# Generated by FakeRAM 2.0
VERSION 5.7 ;
BUSBITCHARS "[]" ;
PROPERTYDEFINITIONS
  MACRO width INTEGER ;
  MACRO depth INTEGER ;
  MACRO banks INTEGER ;
END PROPERTYDEFINITIONS
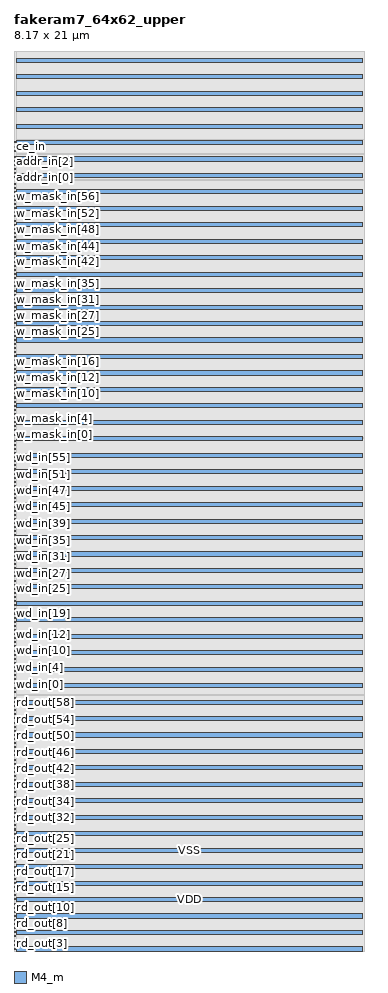
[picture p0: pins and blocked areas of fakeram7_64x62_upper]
MACRO fakeram7_64x62_upper
  PROPERTY width 62 ;
  PROPERTY depth 64 ;
  PROPERTY banks 2 ;
  FOREIGN fakeram7_64x62_upper 0 0 ;
  SYMMETRY X R90 ;
  SIZE 8.170 BY 21.000 ;
  CLASS COVER ;
  PIN rd_out[0]
    DIRECTION OUTPUT ;
    USE SIGNAL ;
    SHAPE ABUTMENT ;
    PORT
      LAYER M4_m ;
      RECT 0.000 0.039 0.024 0.063 ;
    END
  END rd_out[0]
  PIN rd_out[1]
    DIRECTION OUTPUT ;
    USE SIGNAL ;
    SHAPE ABUTMENT ;
    PORT
      LAYER M4_m ;
      RECT 0.000 0.135 0.024 0.159 ;
    END
  END rd_out[1]
  PIN rd_out[2]
    DIRECTION OUTPUT ;
    USE SIGNAL ;
    SHAPE ABUTMENT ;
    PORT
      LAYER M4_m ;
      RECT 0.000 0.231 0.024 0.255 ;
    END
  END rd_out[2]
  PIN rd_out[3]
    DIRECTION OUTPUT ;
    USE SIGNAL ;
    SHAPE ABUTMENT ;
    PORT
      LAYER M4_m ;
      RECT 0.000 0.327 0.024 0.351 ;
    END
  END rd_out[3]
  PIN rd_out[4]
    DIRECTION OUTPUT ;
    USE SIGNAL ;
    SHAPE ABUTMENT ;
    PORT
      LAYER M4_m ;
      RECT 0.000 0.423 0.024 0.447 ;
    END
  END rd_out[4]
  PIN rd_out[5]
    DIRECTION OUTPUT ;
    USE SIGNAL ;
    SHAPE ABUTMENT ;
    PORT
      LAYER M4_m ;
      RECT 0.000 0.519 0.024 0.543 ;
    END
  END rd_out[5]
  PIN rd_out[6]
    DIRECTION OUTPUT ;
    USE SIGNAL ;
    SHAPE ABUTMENT ;
    PORT
      LAYER M4_m ;
      RECT 0.000 0.615 0.024 0.639 ;
    END
  END rd_out[6]
  PIN rd_out[7]
    DIRECTION OUTPUT ;
    USE SIGNAL ;
    SHAPE ABUTMENT ;
    PORT
      LAYER M4_m ;
      RECT 0.000 0.711 0.024 0.735 ;
    END
  END rd_out[7]
  PIN rd_out[8]
    DIRECTION OUTPUT ;
    USE SIGNAL ;
    SHAPE ABUTMENT ;
    PORT
      LAYER M4_m ;
      RECT 0.000 0.807 0.024 0.831 ;
    END
  END rd_out[8]
  PIN rd_out[9]
    DIRECTION OUTPUT ;
    USE SIGNAL ;
    SHAPE ABUTMENT ;
    PORT
      LAYER M4_m ;
      RECT 0.000 0.903 0.024 0.927 ;
    END
  END rd_out[9]
  PIN rd_out[10]
    DIRECTION OUTPUT ;
    USE SIGNAL ;
    SHAPE ABUTMENT ;
    PORT
      LAYER M4_m ;
      RECT 0.000 0.999 0.024 1.023 ;
    END
  END rd_out[10]
  PIN rd_out[11]
    DIRECTION OUTPUT ;
    USE SIGNAL ;
    SHAPE ABUTMENT ;
    PORT
      LAYER M4_m ;
      RECT 0.000 1.095 0.024 1.119 ;
    END
  END rd_out[11]
  PIN rd_out[12]
    DIRECTION OUTPUT ;
    USE SIGNAL ;
    SHAPE ABUTMENT ;
    PORT
      LAYER M4_m ;
      RECT 0.000 1.191 0.024 1.215 ;
    END
  END rd_out[12]
  PIN rd_out[13]
    DIRECTION OUTPUT ;
    USE SIGNAL ;
    SHAPE ABUTMENT ;
    PORT
      LAYER M4_m ;
      RECT 0.000 1.287 0.024 1.311 ;
    END
  END rd_out[13]
  PIN rd_out[14]
    DIRECTION OUTPUT ;
    USE SIGNAL ;
    SHAPE ABUTMENT ;
    PORT
      LAYER M4_m ;
      RECT 0.000 1.383 0.024 1.407 ;
    END
  END rd_out[14]
  PIN rd_out[15]
    DIRECTION OUTPUT ;
    USE SIGNAL ;
    SHAPE ABUTMENT ;
    PORT
      LAYER M4_m ;
      RECT 0.000 1.479 0.024 1.503 ;
    END
  END rd_out[15]
  PIN rd_out[16]
    DIRECTION OUTPUT ;
    USE SIGNAL ;
    SHAPE ABUTMENT ;
    PORT
      LAYER M4_m ;
      RECT 0.000 1.575 0.024 1.599 ;
    END
  END rd_out[16]
  PIN rd_out[17]
    DIRECTION OUTPUT ;
    USE SIGNAL ;
    SHAPE ABUTMENT ;
    PORT
      LAYER M4_m ;
      RECT 0.000 1.671 0.024 1.695 ;
    END
  END rd_out[17]
  PIN rd_out[18]
    DIRECTION OUTPUT ;
    USE SIGNAL ;
    SHAPE ABUTMENT ;
    PORT
      LAYER M4_m ;
      RECT 0.000 1.767 0.024 1.791 ;
    END
  END rd_out[18]
  PIN rd_out[19]
    DIRECTION OUTPUT ;
    USE SIGNAL ;
    SHAPE ABUTMENT ;
    PORT
      LAYER M4_m ;
      RECT 0.000 1.863 0.024 1.887 ;
    END
  END rd_out[19]
  PIN rd_out[20]
    DIRECTION OUTPUT ;
    USE SIGNAL ;
    SHAPE ABUTMENT ;
    PORT
      LAYER M4_m ;
      RECT 0.000 1.959 0.024 1.983 ;
    END
  END rd_out[20]
  PIN rd_out[21]
    DIRECTION OUTPUT ;
    USE SIGNAL ;
    SHAPE ABUTMENT ;
    PORT
      LAYER M4_m ;
      RECT 0.000 2.055 0.024 2.079 ;
    END
  END rd_out[21]
  PIN rd_out[22]
    DIRECTION OUTPUT ;
    USE SIGNAL ;
    SHAPE ABUTMENT ;
    PORT
      LAYER M4_m ;
      RECT 0.000 2.151 0.024 2.175 ;
    END
  END rd_out[22]
  PIN rd_out[23]
    DIRECTION OUTPUT ;
    USE SIGNAL ;
    SHAPE ABUTMENT ;
    PORT
      LAYER M4_m ;
      RECT 0.000 2.247 0.024 2.271 ;
    END
  END rd_out[23]
  PIN rd_out[24]
    DIRECTION OUTPUT ;
    USE SIGNAL ;
    SHAPE ABUTMENT ;
    PORT
      LAYER M4_m ;
      RECT 0.000 2.343 0.024 2.367 ;
    END
  END rd_out[24]
  PIN rd_out[25]
    DIRECTION OUTPUT ;
    USE SIGNAL ;
    SHAPE ABUTMENT ;
    PORT
      LAYER M4_m ;
      RECT 0.000 2.439 0.024 2.463 ;
    END
  END rd_out[25]
  PIN rd_out[26]
    DIRECTION OUTPUT ;
    USE SIGNAL ;
    SHAPE ABUTMENT ;
    PORT
      LAYER M4_m ;
      RECT 0.000 2.535 0.024 2.559 ;
    END
  END rd_out[26]
  PIN rd_out[27]
    DIRECTION OUTPUT ;
    USE SIGNAL ;
    SHAPE ABUTMENT ;
    PORT
      LAYER M4_m ;
      RECT 0.000 2.631 0.024 2.655 ;
    END
  END rd_out[27]
  PIN rd_out[28]
    DIRECTION OUTPUT ;
    USE SIGNAL ;
    SHAPE ABUTMENT ;
    PORT
      LAYER M4_m ;
      RECT 0.000 2.727 0.024 2.751 ;
    END
  END rd_out[28]
  PIN rd_out[29]
    DIRECTION OUTPUT ;
    USE SIGNAL ;
    SHAPE ABUTMENT ;
    PORT
      LAYER M4_m ;
      RECT 0.000 2.823 0.024 2.847 ;
    END
  END rd_out[29]
  PIN rd_out[30]
    DIRECTION OUTPUT ;
    USE SIGNAL ;
    SHAPE ABUTMENT ;
    PORT
      LAYER M4_m ;
      RECT 0.000 2.919 0.024 2.943 ;
    END
  END rd_out[30]
  PIN rd_out[31]
    DIRECTION OUTPUT ;
    USE SIGNAL ;
    SHAPE ABUTMENT ;
    PORT
      LAYER M4_m ;
      RECT 0.000 3.015 0.024 3.039 ;
    END
  END rd_out[31]
  PIN rd_out[32]
    DIRECTION OUTPUT ;
    USE SIGNAL ;
    SHAPE ABUTMENT ;
    PORT
      LAYER M4_m ;
      RECT 0.000 3.111 0.024 3.135 ;
    END
  END rd_out[32]
  PIN rd_out[33]
    DIRECTION OUTPUT ;
    USE SIGNAL ;
    SHAPE ABUTMENT ;
    PORT
      LAYER M4_m ;
      RECT 0.000 3.207 0.024 3.231 ;
    END
  END rd_out[33]
  PIN rd_out[34]
    DIRECTION OUTPUT ;
    USE SIGNAL ;
    SHAPE ABUTMENT ;
    PORT
      LAYER M4_m ;
      RECT 0.000 3.303 0.024 3.327 ;
    END
  END rd_out[34]
  PIN rd_out[35]
    DIRECTION OUTPUT ;
    USE SIGNAL ;
    SHAPE ABUTMENT ;
    PORT
      LAYER M4_m ;
      RECT 0.000 3.399 0.024 3.423 ;
    END
  END rd_out[35]
  PIN rd_out[36]
    DIRECTION OUTPUT ;
    USE SIGNAL ;
    SHAPE ABUTMENT ;
    PORT
      LAYER M4_m ;
      RECT 0.000 3.495 0.024 3.519 ;
    END
  END rd_out[36]
  PIN rd_out[37]
    DIRECTION OUTPUT ;
    USE SIGNAL ;
    SHAPE ABUTMENT ;
    PORT
      LAYER M4_m ;
      RECT 0.000 3.591 0.024 3.615 ;
    END
  END rd_out[37]
  PIN rd_out[38]
    DIRECTION OUTPUT ;
    USE SIGNAL ;
    SHAPE ABUTMENT ;
    PORT
      LAYER M4_m ;
      RECT 0.000 3.687 0.024 3.711 ;
    END
  END rd_out[38]
  PIN rd_out[39]
    DIRECTION OUTPUT ;
    USE SIGNAL ;
    SHAPE ABUTMENT ;
    PORT
      LAYER M4_m ;
      RECT 0.000 3.783 0.024 3.807 ;
    END
  END rd_out[39]
  PIN rd_out[40]
    DIRECTION OUTPUT ;
    USE SIGNAL ;
    SHAPE ABUTMENT ;
    PORT
      LAYER M4_m ;
      RECT 0.000 3.879 0.024 3.903 ;
    END
  END rd_out[40]
  PIN rd_out[41]
    DIRECTION OUTPUT ;
    USE SIGNAL ;
    SHAPE ABUTMENT ;
    PORT
      LAYER M4_m ;
      RECT 0.000 3.975 0.024 3.999 ;
    END
  END rd_out[41]
  PIN rd_out[42]
    DIRECTION OUTPUT ;
    USE SIGNAL ;
    SHAPE ABUTMENT ;
    PORT
      LAYER M4_m ;
      RECT 0.000 4.071 0.024 4.095 ;
    END
  END rd_out[42]
  PIN rd_out[43]
    DIRECTION OUTPUT ;
    USE SIGNAL ;
    SHAPE ABUTMENT ;
    PORT
      LAYER M4_m ;
      RECT 0.000 4.167 0.024 4.191 ;
    END
  END rd_out[43]
  PIN rd_out[44]
    DIRECTION OUTPUT ;
    USE SIGNAL ;
    SHAPE ABUTMENT ;
    PORT
      LAYER M4_m ;
      RECT 0.000 4.263 0.024 4.287 ;
    END
  END rd_out[44]
  PIN rd_out[45]
    DIRECTION OUTPUT ;
    USE SIGNAL ;
    SHAPE ABUTMENT ;
    PORT
      LAYER M4_m ;
      RECT 0.000 4.359 0.024 4.383 ;
    END
  END rd_out[45]
  PIN rd_out[46]
    DIRECTION OUTPUT ;
    USE SIGNAL ;
    SHAPE ABUTMENT ;
    PORT
      LAYER M4_m ;
      RECT 0.000 4.455 0.024 4.479 ;
    END
  END rd_out[46]
  PIN rd_out[47]
    DIRECTION OUTPUT ;
    USE SIGNAL ;
    SHAPE ABUTMENT ;
    PORT
      LAYER M4_m ;
      RECT 0.000 4.551 0.024 4.575 ;
    END
  END rd_out[47]
  PIN rd_out[48]
    DIRECTION OUTPUT ;
    USE SIGNAL ;
    SHAPE ABUTMENT ;
    PORT
      LAYER M4_m ;
      RECT 0.000 4.647 0.024 4.671 ;
    END
  END rd_out[48]
  PIN rd_out[49]
    DIRECTION OUTPUT ;
    USE SIGNAL ;
    SHAPE ABUTMENT ;
    PORT
      LAYER M4_m ;
      RECT 0.000 4.743 0.024 4.767 ;
    END
  END rd_out[49]
  PIN rd_out[50]
    DIRECTION OUTPUT ;
    USE SIGNAL ;
    SHAPE ABUTMENT ;
    PORT
      LAYER M4_m ;
      RECT 0.000 4.839 0.024 4.863 ;
    END
  END rd_out[50]
  PIN rd_out[51]
    DIRECTION OUTPUT ;
    USE SIGNAL ;
    SHAPE ABUTMENT ;
    PORT
      LAYER M4_m ;
      RECT 0.000 4.935 0.024 4.959 ;
    END
  END rd_out[51]
  PIN rd_out[52]
    DIRECTION OUTPUT ;
    USE SIGNAL ;
    SHAPE ABUTMENT ;
    PORT
      LAYER M4_m ;
      RECT 0.000 5.031 0.024 5.055 ;
    END
  END rd_out[52]
  PIN rd_out[53]
    DIRECTION OUTPUT ;
    USE SIGNAL ;
    SHAPE ABUTMENT ;
    PORT
      LAYER M4_m ;
      RECT 0.000 5.127 0.024 5.151 ;
    END
  END rd_out[53]
  PIN rd_out[54]
    DIRECTION OUTPUT ;
    USE SIGNAL ;
    SHAPE ABUTMENT ;
    PORT
      LAYER M4_m ;
      RECT 0.000 5.223 0.024 5.247 ;
    END
  END rd_out[54]
  PIN rd_out[55]
    DIRECTION OUTPUT ;
    USE SIGNAL ;
    SHAPE ABUTMENT ;
    PORT
      LAYER M4_m ;
      RECT 0.000 5.319 0.024 5.343 ;
    END
  END rd_out[55]
  PIN rd_out[56]
    DIRECTION OUTPUT ;
    USE SIGNAL ;
    SHAPE ABUTMENT ;
    PORT
      LAYER M4_m ;
      RECT 0.000 5.415 0.024 5.439 ;
    END
  END rd_out[56]
  PIN rd_out[57]
    DIRECTION OUTPUT ;
    USE SIGNAL ;
    SHAPE ABUTMENT ;
    PORT
      LAYER M4_m ;
      RECT 0.000 5.511 0.024 5.535 ;
    END
  END rd_out[57]
  PIN rd_out[58]
    DIRECTION OUTPUT ;
    USE SIGNAL ;
    SHAPE ABUTMENT ;
    PORT
      LAYER M4_m ;
      RECT 0.000 5.607 0.024 5.631 ;
    END
  END rd_out[58]
  PIN rd_out[59]
    DIRECTION OUTPUT ;
    USE SIGNAL ;
    SHAPE ABUTMENT ;
    PORT
      LAYER M4_m ;
      RECT 0.000 5.703 0.024 5.727 ;
    END
  END rd_out[59]
  PIN rd_out[60]
    DIRECTION OUTPUT ;
    USE SIGNAL ;
    SHAPE ABUTMENT ;
    PORT
      LAYER M4_m ;
      RECT 0.000 5.799 0.024 5.823 ;
    END
  END rd_out[60]
  PIN rd_out[61]
    DIRECTION OUTPUT ;
    USE SIGNAL ;
    SHAPE ABUTMENT ;
    PORT
      LAYER M4_m ;
      RECT 0.000 5.895 0.024 5.919 ;
    END
  END rd_out[61]
  PIN wd_in[0]
    DIRECTION INPUT ;
    USE SIGNAL ;
    SHAPE ABUTMENT ;
    PORT
      LAYER M4_m ;
      RECT 0.000 6.039 0.024 6.063 ;
    END
  END wd_in[0]
  PIN wd_in[1]
    DIRECTION INPUT ;
    USE SIGNAL ;
    SHAPE ABUTMENT ;
    PORT
      LAYER M4_m ;
      RECT 0.000 6.135 0.024 6.159 ;
    END
  END wd_in[1]
  PIN wd_in[2]
    DIRECTION INPUT ;
    USE SIGNAL ;
    SHAPE ABUTMENT ;
    PORT
      LAYER M4_m ;
      RECT 0.000 6.231 0.024 6.255 ;
    END
  END wd_in[2]
  PIN wd_in[3]
    DIRECTION INPUT ;
    USE SIGNAL ;
    SHAPE ABUTMENT ;
    PORT
      LAYER M4_m ;
      RECT 0.000 6.327 0.024 6.351 ;
    END
  END wd_in[3]
  PIN wd_in[4]
    DIRECTION INPUT ;
    USE SIGNAL ;
    SHAPE ABUTMENT ;
    PORT
      LAYER M4_m ;
      RECT 0.000 6.423 0.024 6.447 ;
    END
  END wd_in[4]
  PIN wd_in[5]
    DIRECTION INPUT ;
    USE SIGNAL ;
    SHAPE ABUTMENT ;
    PORT
      LAYER M4_m ;
      RECT 0.000 6.519 0.024 6.543 ;
    END
  END wd_in[5]
  PIN wd_in[6]
    DIRECTION INPUT ;
    USE SIGNAL ;
    SHAPE ABUTMENT ;
    PORT
      LAYER M4_m ;
      RECT 0.000 6.615 0.024 6.639 ;
    END
  END wd_in[6]
  PIN wd_in[7]
    DIRECTION INPUT ;
    USE SIGNAL ;
    SHAPE ABUTMENT ;
    PORT
      LAYER M4_m ;
      RECT 0.000 6.711 0.024 6.735 ;
    END
  END wd_in[7]
  PIN wd_in[8]
    DIRECTION INPUT ;
    USE SIGNAL ;
    SHAPE ABUTMENT ;
    PORT
      LAYER M4_m ;
      RECT 0.000 6.807 0.024 6.831 ;
    END
  END wd_in[8]
  PIN wd_in[9]
    DIRECTION INPUT ;
    USE SIGNAL ;
    SHAPE ABUTMENT ;
    PORT
      LAYER M4_m ;
      RECT 0.000 6.903 0.024 6.927 ;
    END
  END wd_in[9]
  PIN wd_in[10]
    DIRECTION INPUT ;
    USE SIGNAL ;
    SHAPE ABUTMENT ;
    PORT
      LAYER M4_m ;
      RECT 0.000 6.999 0.024 7.023 ;
    END
  END wd_in[10]
  PIN wd_in[11]
    DIRECTION INPUT ;
    USE SIGNAL ;
    SHAPE ABUTMENT ;
    PORT
      LAYER M4_m ;
      RECT 0.000 7.095 0.024 7.119 ;
    END
  END wd_in[11]
  PIN wd_in[12]
    DIRECTION INPUT ;
    USE SIGNAL ;
    SHAPE ABUTMENT ;
    PORT
      LAYER M4_m ;
      RECT 0.000 7.191 0.024 7.215 ;
    END
  END wd_in[12]
  PIN wd_in[13]
    DIRECTION INPUT ;
    USE SIGNAL ;
    SHAPE ABUTMENT ;
    PORT
      LAYER M4_m ;
      RECT 0.000 7.287 0.024 7.311 ;
    END
  END wd_in[13]
  PIN wd_in[14]
    DIRECTION INPUT ;
    USE SIGNAL ;
    SHAPE ABUTMENT ;
    PORT
      LAYER M4_m ;
      RECT 0.000 7.383 0.024 7.407 ;
    END
  END wd_in[14]
  PIN wd_in[15]
    DIRECTION INPUT ;
    USE SIGNAL ;
    SHAPE ABUTMENT ;
    PORT
      LAYER M4_m ;
      RECT 0.000 7.479 0.024 7.503 ;
    END
  END wd_in[15]
  PIN wd_in[16]
    DIRECTION INPUT ;
    USE SIGNAL ;
    SHAPE ABUTMENT ;
    PORT
      LAYER M4_m ;
      RECT 0.000 7.575 0.024 7.599 ;
    END
  END wd_in[16]
  PIN wd_in[17]
    DIRECTION INPUT ;
    USE SIGNAL ;
    SHAPE ABUTMENT ;
    PORT
      LAYER M4_m ;
      RECT 0.000 7.671 0.024 7.695 ;
    END
  END wd_in[17]
  PIN wd_in[18]
    DIRECTION INPUT ;
    USE SIGNAL ;
    SHAPE ABUTMENT ;
    PORT
      LAYER M4_m ;
      RECT 0.000 7.767 0.024 7.791 ;
    END
  END wd_in[18]
  PIN wd_in[19]
    DIRECTION INPUT ;
    USE SIGNAL ;
    SHAPE ABUTMENT ;
    PORT
      LAYER M4_m ;
      RECT 0.000 7.863 0.024 7.887 ;
    END
  END wd_in[19]
  PIN wd_in[20]
    DIRECTION INPUT ;
    USE SIGNAL ;
    SHAPE ABUTMENT ;
    PORT
      LAYER M4_m ;
      RECT 0.000 7.959 0.024 7.983 ;
    END
  END wd_in[20]
  PIN wd_in[21]
    DIRECTION INPUT ;
    USE SIGNAL ;
    SHAPE ABUTMENT ;
    PORT
      LAYER M4_m ;
      RECT 0.000 8.055 0.024 8.079 ;
    END
  END wd_in[21]
  PIN wd_in[22]
    DIRECTION INPUT ;
    USE SIGNAL ;
    SHAPE ABUTMENT ;
    PORT
      LAYER M4_m ;
      RECT 0.000 8.151 0.024 8.175 ;
    END
  END wd_in[22]
  PIN wd_in[23]
    DIRECTION INPUT ;
    USE SIGNAL ;
    SHAPE ABUTMENT ;
    PORT
      LAYER M4_m ;
      RECT 0.000 8.247 0.024 8.271 ;
    END
  END wd_in[23]
  PIN wd_in[24]
    DIRECTION INPUT ;
    USE SIGNAL ;
    SHAPE ABUTMENT ;
    PORT
      LAYER M4_m ;
      RECT 0.000 8.343 0.024 8.367 ;
    END
  END wd_in[24]
  PIN wd_in[25]
    DIRECTION INPUT ;
    USE SIGNAL ;
    SHAPE ABUTMENT ;
    PORT
      LAYER M4_m ;
      RECT 0.000 8.439 0.024 8.463 ;
    END
  END wd_in[25]
  PIN wd_in[26]
    DIRECTION INPUT ;
    USE SIGNAL ;
    SHAPE ABUTMENT ;
    PORT
      LAYER M4_m ;
      RECT 0.000 8.535 0.024 8.559 ;
    END
  END wd_in[26]
  PIN wd_in[27]
    DIRECTION INPUT ;
    USE SIGNAL ;
    SHAPE ABUTMENT ;
    PORT
      LAYER M4_m ;
      RECT 0.000 8.631 0.024 8.655 ;
    END
  END wd_in[27]
  PIN wd_in[28]
    DIRECTION INPUT ;
    USE SIGNAL ;
    SHAPE ABUTMENT ;
    PORT
      LAYER M4_m ;
      RECT 0.000 8.727 0.024 8.751 ;
    END
  END wd_in[28]
  PIN wd_in[29]
    DIRECTION INPUT ;
    USE SIGNAL ;
    SHAPE ABUTMENT ;
    PORT
      LAYER M4_m ;
      RECT 0.000 8.823 0.024 8.847 ;
    END
  END wd_in[29]
  PIN wd_in[30]
    DIRECTION INPUT ;
    USE SIGNAL ;
    SHAPE ABUTMENT ;
    PORT
      LAYER M4_m ;
      RECT 0.000 8.919 0.024 8.943 ;
    END
  END wd_in[30]
  PIN wd_in[31]
    DIRECTION INPUT ;
    USE SIGNAL ;
    SHAPE ABUTMENT ;
    PORT
      LAYER M4_m ;
      RECT 0.000 9.015 0.024 9.039 ;
    END
  END wd_in[31]
  PIN wd_in[32]
    DIRECTION INPUT ;
    USE SIGNAL ;
    SHAPE ABUTMENT ;
    PORT
      LAYER M4_m ;
      RECT 0.000 9.111 0.024 9.135 ;
    END
  END wd_in[32]
  PIN wd_in[33]
    DIRECTION INPUT ;
    USE SIGNAL ;
    SHAPE ABUTMENT ;
    PORT
      LAYER M4_m ;
      RECT 0.000 9.207 0.024 9.231 ;
    END
  END wd_in[33]
  PIN wd_in[34]
    DIRECTION INPUT ;
    USE SIGNAL ;
    SHAPE ABUTMENT ;
    PORT
      LAYER M4_m ;
      RECT 0.000 9.303 0.024 9.327 ;
    END
  END wd_in[34]
  PIN wd_in[35]
    DIRECTION INPUT ;
    USE SIGNAL ;
    SHAPE ABUTMENT ;
    PORT
      LAYER M4_m ;
      RECT 0.000 9.399 0.024 9.423 ;
    END
  END wd_in[35]
  PIN wd_in[36]
    DIRECTION INPUT ;
    USE SIGNAL ;
    SHAPE ABUTMENT ;
    PORT
      LAYER M4_m ;
      RECT 0.000 9.495 0.024 9.519 ;
    END
  END wd_in[36]
  PIN wd_in[37]
    DIRECTION INPUT ;
    USE SIGNAL ;
    SHAPE ABUTMENT ;
    PORT
      LAYER M4_m ;
      RECT 0.000 9.591 0.024 9.615 ;
    END
  END wd_in[37]
  PIN wd_in[38]
    DIRECTION INPUT ;
    USE SIGNAL ;
    SHAPE ABUTMENT ;
    PORT
      LAYER M4_m ;
      RECT 0.000 9.687 0.024 9.711 ;
    END
  END wd_in[38]
  PIN wd_in[39]
    DIRECTION INPUT ;
    USE SIGNAL ;
    SHAPE ABUTMENT ;
    PORT
      LAYER M4_m ;
      RECT 0.000 9.783 0.024 9.807 ;
    END
  END wd_in[39]
  PIN wd_in[40]
    DIRECTION INPUT ;
    USE SIGNAL ;
    SHAPE ABUTMENT ;
    PORT
      LAYER M4_m ;
      RECT 0.000 9.879 0.024 9.903 ;
    END
  END wd_in[40]
  PIN wd_in[41]
    DIRECTION INPUT ;
    USE SIGNAL ;
    SHAPE ABUTMENT ;
    PORT
      LAYER M4_m ;
      RECT 0.000 9.975 0.024 9.999 ;
    END
  END wd_in[41]
  PIN wd_in[42]
    DIRECTION INPUT ;
    USE SIGNAL ;
    SHAPE ABUTMENT ;
    PORT
      LAYER M4_m ;
      RECT 0.000 10.071 0.024 10.095 ;
    END
  END wd_in[42]
  PIN wd_in[43]
    DIRECTION INPUT ;
    USE SIGNAL ;
    SHAPE ABUTMENT ;
    PORT
      LAYER M4_m ;
      RECT 0.000 10.167 0.024 10.191 ;
    END
  END wd_in[43]
  PIN wd_in[44]
    DIRECTION INPUT ;
    USE SIGNAL ;
    SHAPE ABUTMENT ;
    PORT
      LAYER M4_m ;
      RECT 0.000 10.263 0.024 10.287 ;
    END
  END wd_in[44]
  PIN wd_in[45]
    DIRECTION INPUT ;
    USE SIGNAL ;
    SHAPE ABUTMENT ;
    PORT
      LAYER M4_m ;
      RECT 0.000 10.359 0.024 10.383 ;
    END
  END wd_in[45]
  PIN wd_in[46]
    DIRECTION INPUT ;
    USE SIGNAL ;
    SHAPE ABUTMENT ;
    PORT
      LAYER M4_m ;
      RECT 0.000 10.455 0.024 10.479 ;
    END
  END wd_in[46]
  PIN wd_in[47]
    DIRECTION INPUT ;
    USE SIGNAL ;
    SHAPE ABUTMENT ;
    PORT
      LAYER M4_m ;
      RECT 0.000 10.551 0.024 10.575 ;
    END
  END wd_in[47]
  PIN wd_in[48]
    DIRECTION INPUT ;
    USE SIGNAL ;
    SHAPE ABUTMENT ;
    PORT
      LAYER M4_m ;
      RECT 0.000 10.647 0.024 10.671 ;
    END
  END wd_in[48]
  PIN wd_in[49]
    DIRECTION INPUT ;
    USE SIGNAL ;
    SHAPE ABUTMENT ;
    PORT
      LAYER M4_m ;
      RECT 0.000 10.743 0.024 10.767 ;
    END
  END wd_in[49]
  PIN wd_in[50]
    DIRECTION INPUT ;
    USE SIGNAL ;
    SHAPE ABUTMENT ;
    PORT
      LAYER M4_m ;
      RECT 0.000 10.839 0.024 10.863 ;
    END
  END wd_in[50]
  PIN wd_in[51]
    DIRECTION INPUT ;
    USE SIGNAL ;
    SHAPE ABUTMENT ;
    PORT
      LAYER M4_m ;
      RECT 0.000 10.935 0.024 10.959 ;
    END
  END wd_in[51]
  PIN wd_in[52]
    DIRECTION INPUT ;
    USE SIGNAL ;
    SHAPE ABUTMENT ;
    PORT
      LAYER M4_m ;
      RECT 0.000 11.031 0.024 11.055 ;
    END
  END wd_in[52]
  PIN wd_in[53]
    DIRECTION INPUT ;
    USE SIGNAL ;
    SHAPE ABUTMENT ;
    PORT
      LAYER M4_m ;
      RECT 0.000 11.127 0.024 11.151 ;
    END
  END wd_in[53]
  PIN wd_in[54]
    DIRECTION INPUT ;
    USE SIGNAL ;
    SHAPE ABUTMENT ;
    PORT
      LAYER M4_m ;
      RECT 0.000 11.223 0.024 11.247 ;
    END
  END wd_in[54]
  PIN wd_in[55]
    DIRECTION INPUT ;
    USE SIGNAL ;
    SHAPE ABUTMENT ;
    PORT
      LAYER M4_m ;
      RECT 0.000 11.319 0.024 11.343 ;
    END
  END wd_in[55]
  PIN wd_in[56]
    DIRECTION INPUT ;
    USE SIGNAL ;
    SHAPE ABUTMENT ;
    PORT
      LAYER M4_m ;
      RECT 0.000 11.415 0.024 11.439 ;
    END
  END wd_in[56]
  PIN wd_in[57]
    DIRECTION INPUT ;
    USE SIGNAL ;
    SHAPE ABUTMENT ;
    PORT
      LAYER M4_m ;
      RECT 0.000 11.511 0.024 11.535 ;
    END
  END wd_in[57]
  PIN wd_in[58]
    DIRECTION INPUT ;
    USE SIGNAL ;
    SHAPE ABUTMENT ;
    PORT
      LAYER M4_m ;
      RECT 0.000 11.607 0.024 11.631 ;
    END
  END wd_in[58]
  PIN wd_in[59]
    DIRECTION INPUT ;
    USE SIGNAL ;
    SHAPE ABUTMENT ;
    PORT
      LAYER M4_m ;
      RECT 0.000 11.703 0.024 11.727 ;
    END
  END wd_in[59]
  PIN wd_in[60]
    DIRECTION INPUT ;
    USE SIGNAL ;
    SHAPE ABUTMENT ;
    PORT
      LAYER M4_m ;
      RECT 0.000 11.799 0.024 11.823 ;
    END
  END wd_in[60]
  PIN wd_in[61]
    DIRECTION INPUT ;
    USE SIGNAL ;
    SHAPE ABUTMENT ;
    PORT
      LAYER M4_m ;
      RECT 0.000 11.895 0.024 11.919 ;
    END
  END wd_in[61]
  PIN w_mask_in[0]
    DIRECTION INPUT ;
    USE SIGNAL ;
    SHAPE ABUTMENT ;
    PORT
      LAYER M4_m ;
      RECT 0.000 12.039 0.024 12.063 ;
    END
  END w_mask_in[0]
  PIN w_mask_in[1]
    DIRECTION INPUT ;
    USE SIGNAL ;
    SHAPE ABUTMENT ;
    PORT
      LAYER M4_m ;
      RECT 0.000 12.135 0.024 12.159 ;
    END
  END w_mask_in[1]
  PIN w_mask_in[2]
    DIRECTION INPUT ;
    USE SIGNAL ;
    SHAPE ABUTMENT ;
    PORT
      LAYER M4_m ;
      RECT 0.000 12.231 0.024 12.255 ;
    END
  END w_mask_in[2]
  PIN w_mask_in[3]
    DIRECTION INPUT ;
    USE SIGNAL ;
    SHAPE ABUTMENT ;
    PORT
      LAYER M4_m ;
      RECT 0.000 12.327 0.024 12.351 ;
    END
  END w_mask_in[3]
  PIN w_mask_in[4]
    DIRECTION INPUT ;
    USE SIGNAL ;
    SHAPE ABUTMENT ;
    PORT
      LAYER M4_m ;
      RECT 0.000 12.423 0.024 12.447 ;
    END
  END w_mask_in[4]
  PIN w_mask_in[5]
    DIRECTION INPUT ;
    USE SIGNAL ;
    SHAPE ABUTMENT ;
    PORT
      LAYER M4_m ;
      RECT 0.000 12.519 0.024 12.543 ;
    END
  END w_mask_in[5]
  PIN w_mask_in[6]
    DIRECTION INPUT ;
    USE SIGNAL ;
    SHAPE ABUTMENT ;
    PORT
      LAYER M4_m ;
      RECT 0.000 12.615 0.024 12.639 ;
    END
  END w_mask_in[6]
  PIN w_mask_in[7]
    DIRECTION INPUT ;
    USE SIGNAL ;
    SHAPE ABUTMENT ;
    PORT
      LAYER M4_m ;
      RECT 0.000 12.711 0.024 12.735 ;
    END
  END w_mask_in[7]
  PIN w_mask_in[8]
    DIRECTION INPUT ;
    USE SIGNAL ;
    SHAPE ABUTMENT ;
    PORT
      LAYER M4_m ;
      RECT 0.000 12.807 0.024 12.831 ;
    END
  END w_mask_in[8]
  PIN w_mask_in[9]
    DIRECTION INPUT ;
    USE SIGNAL ;
    SHAPE ABUTMENT ;
    PORT
      LAYER M4_m ;
      RECT 0.000 12.903 0.024 12.927 ;
    END
  END w_mask_in[9]
  PIN w_mask_in[10]
    DIRECTION INPUT ;
    USE SIGNAL ;
    SHAPE ABUTMENT ;
    PORT
      LAYER M4_m ;
      RECT 0.000 12.999 0.024 13.023 ;
    END
  END w_mask_in[10]
  PIN w_mask_in[11]
    DIRECTION INPUT ;
    USE SIGNAL ;
    SHAPE ABUTMENT ;
    PORT
      LAYER M4_m ;
      RECT 0.000 13.095 0.024 13.119 ;
    END
  END w_mask_in[11]
  PIN w_mask_in[12]
    DIRECTION INPUT ;
    USE SIGNAL ;
    SHAPE ABUTMENT ;
    PORT
      LAYER M4_m ;
      RECT 0.000 13.191 0.024 13.215 ;
    END
  END w_mask_in[12]
  PIN w_mask_in[13]
    DIRECTION INPUT ;
    USE SIGNAL ;
    SHAPE ABUTMENT ;
    PORT
      LAYER M4_m ;
      RECT 0.000 13.287 0.024 13.311 ;
    END
  END w_mask_in[13]
  PIN w_mask_in[14]
    DIRECTION INPUT ;
    USE SIGNAL ;
    SHAPE ABUTMENT ;
    PORT
      LAYER M4_m ;
      RECT 0.000 13.383 0.024 13.407 ;
    END
  END w_mask_in[14]
  PIN w_mask_in[15]
    DIRECTION INPUT ;
    USE SIGNAL ;
    SHAPE ABUTMENT ;
    PORT
      LAYER M4_m ;
      RECT 0.000 13.479 0.024 13.503 ;
    END
  END w_mask_in[15]
  PIN w_mask_in[16]
    DIRECTION INPUT ;
    USE SIGNAL ;
    SHAPE ABUTMENT ;
    PORT
      LAYER M4_m ;
      RECT 0.000 13.575 0.024 13.599 ;
    END
  END w_mask_in[16]
  PIN w_mask_in[17]
    DIRECTION INPUT ;
    USE SIGNAL ;
    SHAPE ABUTMENT ;
    PORT
      LAYER M4_m ;
      RECT 0.000 13.671 0.024 13.695 ;
    END
  END w_mask_in[17]
  PIN w_mask_in[18]
    DIRECTION INPUT ;
    USE SIGNAL ;
    SHAPE ABUTMENT ;
    PORT
      LAYER M4_m ;
      RECT 0.000 13.767 0.024 13.791 ;
    END
  END w_mask_in[18]
  PIN w_mask_in[19]
    DIRECTION INPUT ;
    USE SIGNAL ;
    SHAPE ABUTMENT ;
    PORT
      LAYER M4_m ;
      RECT 0.000 13.863 0.024 13.887 ;
    END
  END w_mask_in[19]
  PIN w_mask_in[20]
    DIRECTION INPUT ;
    USE SIGNAL ;
    SHAPE ABUTMENT ;
    PORT
      LAYER M4_m ;
      RECT 0.000 13.959 0.024 13.983 ;
    END
  END w_mask_in[20]
  PIN w_mask_in[21]
    DIRECTION INPUT ;
    USE SIGNAL ;
    SHAPE ABUTMENT ;
    PORT
      LAYER M4_m ;
      RECT 0.000 14.055 0.024 14.079 ;
    END
  END w_mask_in[21]
  PIN w_mask_in[22]
    DIRECTION INPUT ;
    USE SIGNAL ;
    SHAPE ABUTMENT ;
    PORT
      LAYER M4_m ;
      RECT 0.000 14.151 0.024 14.175 ;
    END
  END w_mask_in[22]
  PIN w_mask_in[23]
    DIRECTION INPUT ;
    USE SIGNAL ;
    SHAPE ABUTMENT ;
    PORT
      LAYER M4_m ;
      RECT 0.000 14.247 0.024 14.271 ;
    END
  END w_mask_in[23]
  PIN w_mask_in[24]
    DIRECTION INPUT ;
    USE SIGNAL ;
    SHAPE ABUTMENT ;
    PORT
      LAYER M4_m ;
      RECT 0.000 14.343 0.024 14.367 ;
    END
  END w_mask_in[24]
  PIN w_mask_in[25]
    DIRECTION INPUT ;
    USE SIGNAL ;
    SHAPE ABUTMENT ;
    PORT
      LAYER M4_m ;
      RECT 0.000 14.439 0.024 14.463 ;
    END
  END w_mask_in[25]
  PIN w_mask_in[26]
    DIRECTION INPUT ;
    USE SIGNAL ;
    SHAPE ABUTMENT ;
    PORT
      LAYER M4_m ;
      RECT 0.000 14.535 0.024 14.559 ;
    END
  END w_mask_in[26]
  PIN w_mask_in[27]
    DIRECTION INPUT ;
    USE SIGNAL ;
    SHAPE ABUTMENT ;
    PORT
      LAYER M4_m ;
      RECT 0.000 14.631 0.024 14.655 ;
    END
  END w_mask_in[27]
  PIN w_mask_in[28]
    DIRECTION INPUT ;
    USE SIGNAL ;
    SHAPE ABUTMENT ;
    PORT
      LAYER M4_m ;
      RECT 0.000 14.727 0.024 14.751 ;
    END
  END w_mask_in[28]
  PIN w_mask_in[29]
    DIRECTION INPUT ;
    USE SIGNAL ;
    SHAPE ABUTMENT ;
    PORT
      LAYER M4_m ;
      RECT 0.000 14.823 0.024 14.847 ;
    END
  END w_mask_in[29]
  PIN w_mask_in[30]
    DIRECTION INPUT ;
    USE SIGNAL ;
    SHAPE ABUTMENT ;
    PORT
      LAYER M4_m ;
      RECT 0.000 14.919 0.024 14.943 ;
    END
  END w_mask_in[30]
  PIN w_mask_in[31]
    DIRECTION INPUT ;
    USE SIGNAL ;
    SHAPE ABUTMENT ;
    PORT
      LAYER M4_m ;
      RECT 0.000 15.015 0.024 15.039 ;
    END
  END w_mask_in[31]
  PIN w_mask_in[32]
    DIRECTION INPUT ;
    USE SIGNAL ;
    SHAPE ABUTMENT ;
    PORT
      LAYER M4_m ;
      RECT 0.000 15.111 0.024 15.135 ;
    END
  END w_mask_in[32]
  PIN w_mask_in[33]
    DIRECTION INPUT ;
    USE SIGNAL ;
    SHAPE ABUTMENT ;
    PORT
      LAYER M4_m ;
      RECT 0.000 15.207 0.024 15.231 ;
    END
  END w_mask_in[33]
  PIN w_mask_in[34]
    DIRECTION INPUT ;
    USE SIGNAL ;
    SHAPE ABUTMENT ;
    PORT
      LAYER M4_m ;
      RECT 0.000 15.303 0.024 15.327 ;
    END
  END w_mask_in[34]
  PIN w_mask_in[35]
    DIRECTION INPUT ;
    USE SIGNAL ;
    SHAPE ABUTMENT ;
    PORT
      LAYER M4_m ;
      RECT 0.000 15.399 0.024 15.423 ;
    END
  END w_mask_in[35]
  PIN w_mask_in[36]
    DIRECTION INPUT ;
    USE SIGNAL ;
    SHAPE ABUTMENT ;
    PORT
      LAYER M4_m ;
      RECT 0.000 15.495 0.024 15.519 ;
    END
  END w_mask_in[36]
  PIN w_mask_in[37]
    DIRECTION INPUT ;
    USE SIGNAL ;
    SHAPE ABUTMENT ;
    PORT
      LAYER M4_m ;
      RECT 0.000 15.591 0.024 15.615 ;
    END
  END w_mask_in[37]
  PIN w_mask_in[38]
    DIRECTION INPUT ;
    USE SIGNAL ;
    SHAPE ABUTMENT ;
    PORT
      LAYER M4_m ;
      RECT 0.000 15.687 0.024 15.711 ;
    END
  END w_mask_in[38]
  PIN w_mask_in[39]
    DIRECTION INPUT ;
    USE SIGNAL ;
    SHAPE ABUTMENT ;
    PORT
      LAYER M4_m ;
      RECT 0.000 15.783 0.024 15.807 ;
    END
  END w_mask_in[39]
  PIN w_mask_in[40]
    DIRECTION INPUT ;
    USE SIGNAL ;
    SHAPE ABUTMENT ;
    PORT
      LAYER M4_m ;
      RECT 0.000 15.879 0.024 15.903 ;
    END
  END w_mask_in[40]
  PIN w_mask_in[41]
    DIRECTION INPUT ;
    USE SIGNAL ;
    SHAPE ABUTMENT ;
    PORT
      LAYER M4_m ;
      RECT 0.000 15.975 0.024 15.999 ;
    END
  END w_mask_in[41]
  PIN w_mask_in[42]
    DIRECTION INPUT ;
    USE SIGNAL ;
    SHAPE ABUTMENT ;
    PORT
      LAYER M4_m ;
      RECT 0.000 16.071 0.024 16.095 ;
    END
  END w_mask_in[42]
  PIN w_mask_in[43]
    DIRECTION INPUT ;
    USE SIGNAL ;
    SHAPE ABUTMENT ;
    PORT
      LAYER M4_m ;
      RECT 0.000 16.167 0.024 16.191 ;
    END
  END w_mask_in[43]
  PIN w_mask_in[44]
    DIRECTION INPUT ;
    USE SIGNAL ;
    SHAPE ABUTMENT ;
    PORT
      LAYER M4_m ;
      RECT 0.000 16.263 0.024 16.287 ;
    END
  END w_mask_in[44]
  PIN w_mask_in[45]
    DIRECTION INPUT ;
    USE SIGNAL ;
    SHAPE ABUTMENT ;
    PORT
      LAYER M4_m ;
      RECT 0.000 16.359 0.024 16.383 ;
    END
  END w_mask_in[45]
  PIN w_mask_in[46]
    DIRECTION INPUT ;
    USE SIGNAL ;
    SHAPE ABUTMENT ;
    PORT
      LAYER M4_m ;
      RECT 0.000 16.455 0.024 16.479 ;
    END
  END w_mask_in[46]
  PIN w_mask_in[47]
    DIRECTION INPUT ;
    USE SIGNAL ;
    SHAPE ABUTMENT ;
    PORT
      LAYER M4_m ;
      RECT 0.000 16.551 0.024 16.575 ;
    END
  END w_mask_in[47]
  PIN w_mask_in[48]
    DIRECTION INPUT ;
    USE SIGNAL ;
    SHAPE ABUTMENT ;
    PORT
      LAYER M4_m ;
      RECT 0.000 16.647 0.024 16.671 ;
    END
  END w_mask_in[48]
  PIN w_mask_in[49]
    DIRECTION INPUT ;
    USE SIGNAL ;
    SHAPE ABUTMENT ;
    PORT
      LAYER M4_m ;
      RECT 0.000 16.743 0.024 16.767 ;
    END
  END w_mask_in[49]
  PIN w_mask_in[50]
    DIRECTION INPUT ;
    USE SIGNAL ;
    SHAPE ABUTMENT ;
    PORT
      LAYER M4_m ;
      RECT 0.000 16.839 0.024 16.863 ;
    END
  END w_mask_in[50]
  PIN w_mask_in[51]
    DIRECTION INPUT ;
    USE SIGNAL ;
    SHAPE ABUTMENT ;
    PORT
      LAYER M4_m ;
      RECT 0.000 16.935 0.024 16.959 ;
    END
  END w_mask_in[51]
  PIN w_mask_in[52]
    DIRECTION INPUT ;
    USE SIGNAL ;
    SHAPE ABUTMENT ;
    PORT
      LAYER M4_m ;
      RECT 0.000 17.031 0.024 17.055 ;
    END
  END w_mask_in[52]
  PIN w_mask_in[53]
    DIRECTION INPUT ;
    USE SIGNAL ;
    SHAPE ABUTMENT ;
    PORT
      LAYER M4_m ;
      RECT 0.000 17.127 0.024 17.151 ;
    END
  END w_mask_in[53]
  PIN w_mask_in[54]
    DIRECTION INPUT ;
    USE SIGNAL ;
    SHAPE ABUTMENT ;
    PORT
      LAYER M4_m ;
      RECT 0.000 17.223 0.024 17.247 ;
    END
  END w_mask_in[54]
  PIN w_mask_in[55]
    DIRECTION INPUT ;
    USE SIGNAL ;
    SHAPE ABUTMENT ;
    PORT
      LAYER M4_m ;
      RECT 0.000 17.319 0.024 17.343 ;
    END
  END w_mask_in[55]
  PIN w_mask_in[56]
    DIRECTION INPUT ;
    USE SIGNAL ;
    SHAPE ABUTMENT ;
    PORT
      LAYER M4_m ;
      RECT 0.000 17.415 0.024 17.439 ;
    END
  END w_mask_in[56]
  PIN w_mask_in[57]
    DIRECTION INPUT ;
    USE SIGNAL ;
    SHAPE ABUTMENT ;
    PORT
      LAYER M4_m ;
      RECT 0.000 17.511 0.024 17.535 ;
    END
  END w_mask_in[57]
  PIN w_mask_in[58]
    DIRECTION INPUT ;
    USE SIGNAL ;
    SHAPE ABUTMENT ;
    PORT
      LAYER M4_m ;
      RECT 0.000 17.607 0.024 17.631 ;
    END
  END w_mask_in[58]
  PIN w_mask_in[59]
    DIRECTION INPUT ;
    USE SIGNAL ;
    SHAPE ABUTMENT ;
    PORT
      LAYER M4_m ;
      RECT 0.000 17.703 0.024 17.727 ;
    END
  END w_mask_in[59]
  PIN w_mask_in[60]
    DIRECTION INPUT ;
    USE SIGNAL ;
    SHAPE ABUTMENT ;
    PORT
      LAYER M4_m ;
      RECT 0.000 17.799 0.024 17.823 ;
    END
  END w_mask_in[60]
  PIN w_mask_in[61]
    DIRECTION INPUT ;
    USE SIGNAL ;
    SHAPE ABUTMENT ;
    PORT
      LAYER M4_m ;
      RECT 0.000 17.895 0.024 17.919 ;
    END
  END w_mask_in[61]
  PIN addr_in[0]
    DIRECTION INPUT ;
    USE SIGNAL ;
    SHAPE ABUTMENT ;
    PORT
      LAYER M4_m ;
      RECT 0.000 18.039 0.024 18.063 ;
    END
  END addr_in[0]
  PIN addr_in[1]
    DIRECTION INPUT ;
    USE SIGNAL ;
    SHAPE ABUTMENT ;
    PORT
      LAYER M4_m ;
      RECT 0.000 18.135 0.024 18.159 ;
    END
  END addr_in[1]
  PIN addr_in[2]
    DIRECTION INPUT ;
    USE SIGNAL ;
    SHAPE ABUTMENT ;
    PORT
      LAYER M4_m ;
      RECT 0.000 18.231 0.024 18.255 ;
    END
  END addr_in[2]
  PIN addr_in[3]
    DIRECTION INPUT ;
    USE SIGNAL ;
    SHAPE ABUTMENT ;
    PORT
      LAYER M4_m ;
      RECT 0.000 18.327 0.024 18.351 ;
    END
  END addr_in[3]
  PIN addr_in[4]
    DIRECTION INPUT ;
    USE SIGNAL ;
    SHAPE ABUTMENT ;
    PORT
      LAYER M4_m ;
      RECT 0.000 18.423 0.024 18.447 ;
    END
  END addr_in[4]
  PIN addr_in[5]
    DIRECTION INPUT ;
    USE SIGNAL ;
    SHAPE ABUTMENT ;
    PORT
      LAYER M4_m ;
      RECT 0.000 18.519 0.024 18.543 ;
    END
  END addr_in[5]
  PIN we_in
    DIRECTION INPUT ;
    USE SIGNAL ;
    SHAPE ABUTMENT ;
    PORT
      LAYER M4_m ;
      RECT 0.000 18.663 0.024 18.687 ;
    END
  END we_in
  PIN ce_in
    DIRECTION INPUT ;
    USE SIGNAL ;
    SHAPE ABUTMENT ;
    PORT
      LAYER M4_m ;
      RECT 0.000 18.759 0.024 18.783 ;
    END
  END ce_in
  PIN clk
    DIRECTION INPUT ;
    USE SIGNAL ;
    SHAPE ABUTMENT ;
    PORT
      LAYER M4_m ;
      RECT 0.000 18.855 0.024 18.879 ;
    END
  END clk
  PIN VSS
    DIRECTION INOUT ;
    USE GROUND ;
    PORT
      LAYER M4_m ;
      RECT 0.048 0.000 8.122 0.096 ;
      RECT 0.048 0.768 8.122 0.864 ;
      RECT 0.048 1.536 8.122 1.632 ;
      RECT 0.048 2.304 8.122 2.400 ;
      RECT 0.048 3.072 8.122 3.168 ;
      RECT 0.048 3.840 8.122 3.936 ;
      RECT 0.048 4.608 8.122 4.704 ;
      RECT 0.048 5.376 8.122 5.472 ;
      RECT 0.048 6.144 8.122 6.240 ;
      RECT 0.048 6.912 8.122 7.008 ;
      RECT 0.048 7.680 8.122 7.776 ;
      RECT 0.048 8.448 8.122 8.544 ;
      RECT 0.048 9.216 8.122 9.312 ;
      RECT 0.048 9.984 8.122 10.080 ;
      RECT 0.048 10.752 8.122 10.848 ;
      RECT 0.048 11.520 8.122 11.616 ;
      RECT 0.048 12.288 8.122 12.384 ;
      RECT 0.048 13.056 8.122 13.152 ;
      RECT 0.048 13.824 8.122 13.920 ;
      RECT 0.048 14.592 8.122 14.688 ;
      RECT 0.048 15.360 8.122 15.456 ;
      RECT 0.048 16.128 8.122 16.224 ;
      RECT 0.048 16.896 8.122 16.992 ;
      RECT 0.048 17.664 8.122 17.760 ;
      RECT 0.048 18.432 8.122 18.528 ;
      RECT 0.048 19.200 8.122 19.296 ;
      RECT 0.048 19.968 8.122 20.064 ;
      RECT 0.048 20.736 8.122 20.832 ;
    END
  END VSS
  PIN VDD
    DIRECTION INOUT ;
    USE POWER ;
    PORT
      LAYER M4_m ;
      RECT 0.048 0.384 8.122 0.480 ;
      RECT 0.048 1.152 8.122 1.248 ;
      RECT 0.048 1.920 8.122 2.016 ;
      RECT 0.048 2.688 8.122 2.784 ;
      RECT 0.048 3.456 8.122 3.552 ;
      RECT 0.048 4.224 8.122 4.320 ;
      RECT 0.048 4.992 8.122 5.088 ;
      RECT 0.048 5.760 8.122 5.856 ;
      RECT 0.048 6.528 8.122 6.624 ;
      RECT 0.048 7.296 8.122 7.392 ;
      RECT 0.048 8.064 8.122 8.160 ;
      RECT 0.048 8.832 8.122 8.928 ;
      RECT 0.048 9.600 8.122 9.696 ;
      RECT 0.048 10.368 8.122 10.464 ;
      RECT 0.048 11.136 8.122 11.232 ;
      RECT 0.048 11.904 8.122 12.000 ;
      RECT 0.048 12.672 8.122 12.768 ;
      RECT 0.048 13.440 8.122 13.536 ;
      RECT 0.048 14.208 8.122 14.304 ;
      RECT 0.048 14.976 8.122 15.072 ;
      RECT 0.048 15.744 8.122 15.840 ;
      RECT 0.048 16.512 8.122 16.608 ;
      RECT 0.048 17.280 8.122 17.376 ;
      RECT 0.048 18.048 8.122 18.144 ;
      RECT 0.048 18.816 8.122 18.912 ;
      RECT 0.048 19.584 8.122 19.680 ;
      RECT 0.048 20.352 8.122 20.448 ;
    END
  END VDD
  OBS
    LAYER M1_m ;
    RECT 0 0 8.170 21.000 ;
    LAYER M2_m ;
    RECT 0 0 8.170 21.000 ;
    LAYER M3_m ;
    RECT 0.059 0.000 8.170 21.000 ;
    LAYER M4_m ;
    RECT 0.059 5.967 8.170 5.991 ;
    RECT 0.059 11.967 8.170 11.991 ;
    RECT 0.059 17.967 8.170 17.991 ;
    RECT 0.059 18.591 8.170 18.615 ;
    RECT 0.059 18.927 8.170 21.000 ;
  END
END fakeram7_64x62_upper

END LIBRARY
